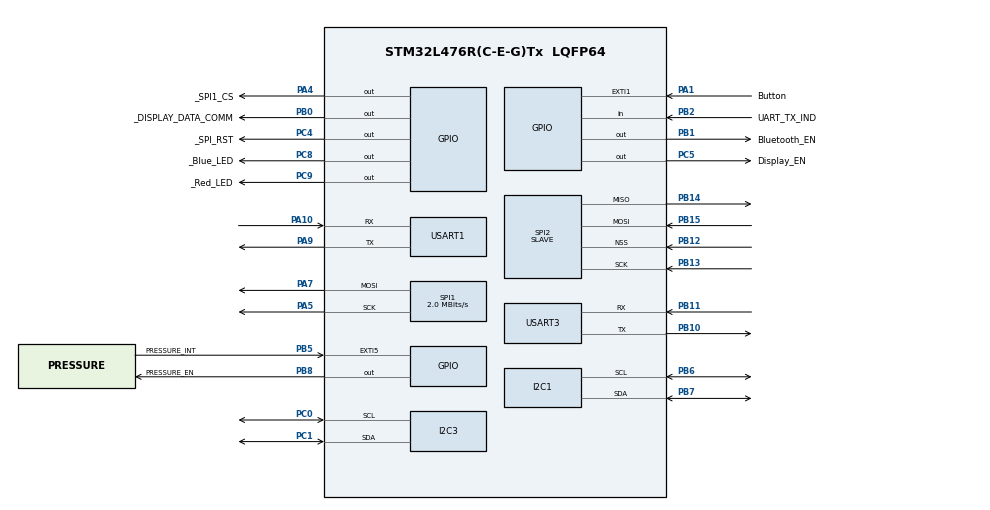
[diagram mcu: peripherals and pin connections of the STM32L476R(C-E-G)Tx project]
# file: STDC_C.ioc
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I2C1.Timing=0x00100D14
I2C3.Timing=0x00100D14
Mcu.Family=STM32L4
Mcu.Name=STM32L476R(C-E-G)Tx
Mcu.Package=LQFP64
NVIC.PriorityGroup=NVIC_PRIORITYGROUP_4
PA1.GPIO_Label=Button
PA1.GPIO_ModeDefaultEXTI=GPIO_MODE_IT_FALLING
PA1.GPIO_PuPd=GPIO_PULLUP
PA1.Signal=GPXTI1
PA10.Mode=Asynchronous
PA10.Signal=USART1_RX
PA13\ (JTMS-SWDIO).Mode=JTAG_5_pins
PA13\ (JTMS-SWDIO).Signal=SYS_JTMS-SWDIO
PA14\ (JTCK-SWCLK).Mode=JTAG_5_pins
PA14\ (JTCK-SWCLK).Signal=SYS_JTCK-SWCLK
PA15\ (JTDI).Mode=JTAG_5_pins
PA15\ (JTDI).Signal=SYS_JTDI
PA4.GPIO_Label=_SPI1_CS
PA4.Signal=GPIO_Output
PA5.Mode=TX_Only_Simplex_Unidirect_Master
PA5.Signal=SPI1_SCK
PA7.Mode=TX_Only_Simplex_Unidirect_Master
PA7.Signal=SPI1_MOSI
PA9.Mode=Asynchronous
PA9.Signal=USART1_TX
PB0.GPIO_Label=_DISPLAY_DATA_COMM
PB0.Signal=GPIO_Output
PB1.GPIO_Label=Bluetooth_EN
PB1.Signal=GPIO_Output
PB10.Mode=Asynchronous
PB10.Signal=USART3_TX
PB11.Mode=Asynchronous
PB11.Signal=USART3_RX
PB12.Mode=NSS_Signal_Hard_Input
PB12.Signal=SPI2_NSS
PB13.Mode=Full_Duplex_Slave
PB13.Signal=SPI2_SCK
PB14.Mode=Full_Duplex_Slave
PB14.Signal=SPI2_MISO
PB15.Mode=Full_Duplex_Slave
PB15.Signal=SPI2_MOSI
PB2.GPIO_Label=UART_TX_IND
PB2.Signal=GPIO_Input
PB3\ (JTDO-TRACESWO).Mode=JTAG_5_pins
PB3\ (JTDO-TRACESWO).Signal=SYS_JTDO-SWO
PB4\ (NJTRST).Mode=JTAG_5_pins
PB4\ (NJTRST).Signal=SYS_JTRST
PB5.GPIO_Label=PRESSURE_INT
PB5.Signal=GPXTI5
PB6.Mode=I2C
PB6.Signal=I2C1_SCL
PB7.Mode=I2C
PB7.Signal=I2C1_SDA
PB8.GPIO_Label=PRESSURE_EN
PB8.Signal=GPIO_Output
PC0.Mode=I2C
PC0.Signal=I2C3_SCL
PC1.Mode=I2C
PC1.Signal=I2C3_SDA
PC14-OSC32_IN\ (PC14).Mode=LSE-External-Oscillator
PC14-OSC32_IN\ (PC14).Signal=RCC_OSC32_IN
PC15-OSC32_OUT\ (PC15).Mode=LSE-External-Oscillator
PC15-OSC32_OUT\ (PC15).Signal=RCC_OSC32_OUT
PC4.GPIO_Label=_SPI_RST
PC4.Signal=GPIO_Output
PC5.GPIO_Label=Display_EN
PC5.Signal=GPIO_Output
PC8.GPIO_Label=_Blue_LED
PC8.Signal=GPIO_Output
PC9.GPIO_Label=_Red_LED
PC9.Signal=GPIO_Output
ProjectManager.HeapSize=0x200
ProjectManager.StackSize=0x400
ProjectManager.TargetToolchain=CMake
RCC.ADCFreq_Value=16000000
RCC.AHBFreq_Value=4000000
RCC.APB1Freq_Value=4000000
RCC.APB1TimFreq_Value=4000000
RCC.APB2Freq_Value=4000000
RCC.APB2TimFreq_Value=4000000
RCC.CortexFreq_Value=4000000
RCC.HCLKFreq_Value=4000000
RCC.HSE_VALUE=8000000
RCC.HSI_VALUE=16000000
RCC.MSI_VALUE=4000000
RCC.PLLM=4
RCC.PLLR=RCC_PLLR_DIV8
RCC.PLLSourceVirtual=RCC_PLLSOURCE_HSI
RCC.RTCClockSelection=RCC_RTCCLKSOURCE_LSE
RCC.SYSCLKFreq_VALUE=4000000
RCC.SYSCLKSource=RCC_SYSCLKSOURCE_PLLCLK
RCC.USBFreq_Value=16000000
RCC.VCOOutputFreq_Value=32000000
RTC.WakeUpClock-WakeUp=RTC_WAKEUPCLOCK_CK_SPRE_16BITS
RTC.WakeUpCounter-WakeUp=4
SPI1.BaudRatePrescaler=SPI_BAUDRATEPRESCALER_2
SPI1.CalculateBaudRate=2.0 MBits/s
SPI1.Direction=SPI_DIRECTION_2LINES
SPI1.Mode=SPI_MODE_MASTER
SPI1.VirtualType=VM_MASTER
SPI2.DataSize=SPI_DATASIZE_8BIT
SPI2.Direction=SPI_DIRECTION_2LINES
SPI2.Mode=SPI_MODE_SLAVE
SPI2.VirtualNSS=VM_NSSHARD
SPI2.VirtualType=VM_SLAVE
USART1.VirtualMode-Asynchronous=VM_ASYNC
USART3.VirtualMode-Asynchronous=VM_ASYNC
VP_RTC_VS_RTC_Activate.Mode=RTC_Enabled
VP_RTC_VS_RTC_Calendar.Mode=RTC_Calendar
VP_RTC_VS_RTC_WakeUp_intern.Mode=WakeUp
board=custom

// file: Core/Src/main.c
/* USER CODE BEGIN Header */
/**
  ******************************************************************************
  * @file           : main.c
  * @brief          : Main program body
  ******************************************************************************
  * @attention
  *
  * Copyright (c) 2026 STMicroelectronics.
  * All rights reserved.
  *
  * This software is licensed under terms that can be found in the LICENSE file
  * in the root directory of this software component.
  * If no LICENSE file comes with this software, it is provided AS-IS.
  *
  ******************************************************************************
  */
/* USER CODE END Header */
#include "main.h"

I2C_HandleTypeDef hi2c1;
I2C_HandleTypeDef hi2c3;

RTC_HandleTypeDef hrtc;

SPI_HandleTypeDef hspi1;
SPI_HandleTypeDef hspi2;

UART_HandleTypeDef huart1;
UART_HandleTypeDef huart3;

void SystemClock_Config(void);
static void MX_GPIO_Init(void);
static void MX_I2C1_Init(void);
static void MX_SPI1_Init(void);
static void MX_USART1_UART_Init(void);
static void MX_RTC_Init(void);
static void MX_USART3_UART_Init(void);
static void MX_SPI2_Init(void);
static void MX_I2C3_Init(void);

int main(void)
{

  /* MCU Configuration--------------------------------------------------------*/

  /* Reset of all peripherals, Initializes the Flash interface and the Systick. */
  HAL_Init();

  /* Configure the system clock */
  SystemClock_Config();

  /* Initialize all configured peripherals */
  MX_GPIO_Init();
  MX_I2C1_Init();
  MX_SPI1_Init();
  MX_USART1_UART_Init();
  MX_RTC_Init();
  MX_USART3_UART_Init();
  MX_SPI2_Init();
  MX_I2C3_Init();

  /* Infinite loop */
  while (1)
  {

  }
}

void SystemClock_Config(void)
{
  RCC_OscInitTypeDef RCC_OscInitStruct = {0};
  RCC_ClkInitTypeDef RCC_ClkInitStruct = {0};

  /** Configure the main internal regulator output voltage
  */
  if (HAL_PWREx_ControlVoltageScaling(PWR_REGULATOR_VOLTAGE_SCALE1) != HAL_OK)
  {
    Error_Handler();
  }

  /** Configure LSE Drive Capability
  */
  HAL_PWR_EnableBkUpAccess();
  __HAL_RCC_LSEDRIVE_CONFIG(RCC_LSEDRIVE_LOW);

  /** Initializes the RCC Oscillators according to the specified parameters
  * in the RCC_OscInitTypeDef structure.
  */
  RCC_OscInitStruct.OscillatorType = RCC_OSCILLATORTYPE_HSI|RCC_OSCILLATORTYPE_LSE;
  RCC_OscInitStruct.LSEState = RCC_LSE_ON;
  RCC_OscInitStruct.HSIState = RCC_HSI_ON;
  RCC_OscInitStruct.HSICalibrationValue = RCC_HSICALIBRATION_DEFAULT;
  RCC_OscInitStruct.PLL.PLLState = RCC_PLL_ON;
  RCC_OscInitStruct.PLL.PLLSource = RCC_PLLSOURCE_HSI;
  RCC_OscInitStruct.PLL.PLLM = 1;
  RCC_OscInitStruct.PLL.PLLN = 8;
  RCC_OscInitStruct.PLL.PLLP = RCC_PLLP_DIV7;
  RCC_OscInitStruct.PLL.PLLQ = RCC_PLLQ_DIV2;
  RCC_OscInitStruct.PLL.PLLR = RCC_PLLR_DIV4;
  if (HAL_RCC_OscConfig(&RCC_OscInitStruct) != HAL_OK)
  {
    Error_Handler();
  }

  /** Initializes the CPU, AHB and APB buses clocks
  */
  RCC_ClkInitStruct.ClockType = RCC_CLOCKTYPE_HCLK|RCC_CLOCKTYPE_SYSCLK
                              |RCC_CLOCKTYPE_PCLK1|RCC_CLOCKTYPE_PCLK2;
  RCC_ClkInitStruct.SYSCLKSource = RCC_SYSCLKSOURCE_PLLCLK;
  RCC_ClkInitStruct.AHBCLKDivider = RCC_SYSCLK_DIV1;
  RCC_ClkInitStruct.APB1CLKDivider = RCC_HCLK_DIV1;
  RCC_ClkInitStruct.APB2CLKDivider = RCC_HCLK_DIV1;

  if (HAL_RCC_ClockConfig(&RCC_ClkInitStruct, FLASH_LATENCY_1) != HAL_OK)
  {
    Error_Handler();
  }
}

static void MX_I2C1_Init(void)
{

  hi2c1.Instance = I2C1;
  hi2c1.Init.Timing = 0x00B07CB4;
  hi2c1.Init.OwnAddress1 = 0;
  hi2c1.Init.AddressingMode = I2C_ADDRESSINGMODE_7BIT;
  hi2c1.Init.DualAddressMode = I2C_DUALADDRESS_DISABLE;
  hi2c1.Init.OwnAddress2 = 0;
  hi2c1.Init.OwnAddress2Masks = I2C_OA2_NOMASK;
  hi2c1.Init.GeneralCallMode = I2C_GENERALCALL_DISABLE;
  hi2c1.Init.NoStretchMode = I2C_NOSTRETCH_DISABLE;
  if (HAL_I2C_Init(&hi2c1) != HAL_OK)
  {
    Error_Handler();
  }

  /** Configure Analogue filter
  */
  if (HAL_I2CEx_ConfigAnalogFilter(&hi2c1, I2C_ANALOGFILTER_ENABLE) != HAL_OK)
  {
    Error_Handler();
  }

  /** Configure Digital filter
  */
  if (HAL_I2CEx_ConfigDigitalFilter(&hi2c1, 0) != HAL_OK)
  {
    Error_Handler();
  }

}

static void MX_I2C3_Init(void)
{

  hi2c3.Instance = I2C3;
  hi2c3.Init.Timing = 0x00B07CB4;
  hi2c3.Init.OwnAddress1 = 0;
  hi2c3.Init.AddressingMode = I2C_ADDRESSINGMODE_7BIT;
  hi2c3.Init.DualAddressMode = I2C_DUALADDRESS_DISABLE;
  hi2c3.Init.OwnAddress2 = 0;
  hi2c3.Init.OwnAddress2Masks = I2C_OA2_NOMASK;
  hi2c3.Init.GeneralCallMode = I2C_GENERALCALL_DISABLE;
  hi2c3.Init.NoStretchMode = I2C_NOSTRETCH_DISABLE;
  if (HAL_I2C_Init(&hi2c3) != HAL_OK)
  {
    Error_Handler();
  }

  /** Configure Analogue filter
  */
  if (HAL_I2CEx_ConfigAnalogFilter(&hi2c3, I2C_ANALOGFILTER_ENABLE) != HAL_OK)
  {
    Error_Handler();
  }

  /** Configure Digital filter
  */
  if (HAL_I2CEx_ConfigDigitalFilter(&hi2c3, 0) != HAL_OK)
  {
    Error_Handler();
  }

}

static void MX_RTC_Init(void)
{

  RTC_TimeTypeDef sTime = {0};
  RTC_DateTypeDef sDate = {0};

  /** Initialize RTC Only
  */
  hrtc.Instance = RTC;
  hrtc.Init.HourFormat = RTC_HOURFORMAT_24;
  hrtc.Init.AsynchPrediv = 127;
  hrtc.Init.SynchPrediv = 255;
  hrtc.Init.OutPut = RTC_OUTPUT_DISABLE;
  hrtc.Init.OutPutRemap = RTC_OUTPUT_REMAP_NONE;
  hrtc.Init.OutPutPolarity = RTC_OUTPUT_POLARITY_HIGH;
  hrtc.Init.OutPutType = RTC_OUTPUT_TYPE_OPENDRAIN;
  if (HAL_RTC_Init(&hrtc) != HAL_OK)
  {
    Error_Handler();
  }

  /** Initialize RTC and set the Time and Date
  */
  sTime.Hours = 0x0;
  sTime.Minutes = 0x0;
  sTime.Seconds = 0x0;
  sTime.DayLightSaving = RTC_DAYLIGHTSAVING_NONE;
  sTime.StoreOperation = RTC_STOREOPERATION_RESET;
  if (HAL_RTC_SetTime(&hrtc, &sTime, RTC_FORMAT_BCD) != HAL_OK)
  {
    Error_Handler();
  }
  sDate.WeekDay = RTC_WEEKDAY_MONDAY;
  sDate.Month = RTC_MONTH_JANUARY;
  sDate.Date = 0x1;
  sDate.Year = 0x0;

  if (HAL_RTC_SetDate(&hrtc, &sDate, RTC_FORMAT_BCD) != HAL_OK)
  {
    Error_Handler();
  }

  /** Enable the WakeUp
  */
  if (HAL_RTCEx_SetWakeUpTimer(&hrtc, 4, RTC_WAKEUPCLOCK_CK_SPRE_16BITS) != HAL_OK)
  {
    Error_Handler();
  }

}

static void MX_SPI1_Init(void)
{

  /* SPI1 parameter configuration*/
  hspi1.Instance = SPI1;
  hspi1.Init.Mode = SPI_MODE_MASTER;
  hspi1.Init.Direction = SPI_DIRECTION_2LINES;
  hspi1.Init.DataSize = SPI_DATASIZE_4BIT;
  hspi1.Init.CLKPolarity = SPI_POLARITY_LOW;
  hspi1.Init.CLKPhase = SPI_PHASE_1EDGE;
  hspi1.Init.NSS = SPI_NSS_SOFT;
  hspi1.Init.BaudRatePrescaler = SPI_BAUDRATEPRESCALER_2;
  hspi1.Init.FirstBit = SPI_FIRSTBIT_MSB;
  hspi1.Init.TIMode = SPI_TIMODE_DISABLE;
  hspi1.Init.CRCCalculation = SPI_CRCCALCULATION_DISABLE;
  hspi1.Init.CRCPolynomial = 7;
  hspi1.Init.CRCLength = SPI_CRC_LENGTH_DATASIZE;
  hspi1.Init.NSSPMode = SPI_NSS_PULSE_ENABLE;
  if (HAL_SPI_Init(&hspi1) != HAL_OK)
  {
    Error_Handler();
  }

}

static void MX_SPI2_Init(void)
{

  /* SPI2 parameter configuration*/
  hspi2.Instance = SPI2;
  hspi2.Init.Mode = SPI_MODE_SLAVE;
  hspi2.Init.Direction = SPI_DIRECTION_2LINES;
  hspi2.Init.DataSize = SPI_DATASIZE_8BIT;
  hspi2.Init.CLKPolarity = SPI_POLARITY_LOW;
  hspi2.Init.CLKPhase = SPI_PHASE_1EDGE;
  hspi2.Init.NSS = SPI_NSS_HARD_INPUT;
  hspi2.Init.FirstBit = SPI_FIRSTBIT_MSB;
  hspi2.Init.TIMode = SPI_TIMODE_DISABLE;
  hspi2.Init.CRCCalculation = SPI_CRCCALCULATION_DISABLE;
  hspi2.Init.CRCPolynomial = 7;
  hspi2.Init.CRCLength = SPI_CRC_LENGTH_DATASIZE;
  hspi2.Init.NSSPMode = SPI_NSS_PULSE_DISABLE;
  if (HAL_SPI_Init(&hspi2) != HAL_OK)
  {
    Error_Handler();
  }

}

static void MX_USART1_UART_Init(void)
{

  huart1.Instance = USART1;
  huart1.Init.BaudRate = 115200;
  huart1.Init.WordLength = UART_WORDLENGTH_8B;
  huart1.Init.StopBits = UART_STOPBITS_1;
  huart1.Init.Parity = UART_PARITY_NONE;
  huart1.Init.Mode = UART_MODE_TX_RX;
  huart1.Init.HwFlowCtl = UART_HWCONTROL_NONE;
  huart1.Init.OverSampling = UART_OVERSAMPLING_16;
  huart1.Init.OneBitSampling = UART_ONE_BIT_SAMPLE_DISABLE;
  huart1.AdvancedInit.AdvFeatureInit = UART_ADVFEATURE_NO_INIT;
  if (HAL_UART_Init(&huart1) != HAL_OK)
  {
    Error_Handler();
  }

}

static void MX_USART3_UART_Init(void)
{

  huart3.Instance = USART3;
  huart3.Init.BaudRate = 115200;
  huart3.Init.WordLength = UART_WORDLENGTH_8B;
  huart3.Init.StopBits = UART_STOPBITS_1;
  huart3.Init.Parity = UART_PARITY_NONE;
  huart3.Init.Mode = UART_MODE_TX_RX;
  huart3.Init.HwFlowCtl = UART_HWCONTROL_NONE;
  huart3.Init.OverSampling = UART_OVERSAMPLING_16;
  huart3.Init.OneBitSampling = UART_ONE_BIT_SAMPLE_DISABLE;
  huart3.AdvancedInit.AdvFeatureInit = UART_ADVFEATURE_NO_INIT;
  if (HAL_UART_Init(&huart3) != HAL_OK)
  {
    Error_Handler();
  }

}

static void MX_GPIO_Init(void)
{
  GPIO_InitTypeDef GPIO_InitStruct = {0};

  /* GPIO Ports Clock Enable */
  __HAL_RCC_GPIOC_CLK_ENABLE();
  __HAL_RCC_GPIOA_CLK_ENABLE();
  __HAL_RCC_GPIOB_CLK_ENABLE();

  /*Configure GPIO pin Output Level */
  HAL_GPIO_WritePin(_SPI1_CS_GPIO_Port, _SPI1_CS_Pin, GPIO_PIN_RESET);

  /*Configure GPIO pin Output Level */
  HAL_GPIO_WritePin(GPIOC, _SPI_RST_Pin|Display_EN_Pin|_Blue_LED_Pin|_Red_LED_Pin, GPIO_PIN_RESET);

  /*Configure GPIO pin Output Level */
  HAL_GPIO_WritePin(GPIOB, _DISPLAY_DATA_COMM_Pin|PRESSURE_EN_Pin, GPIO_PIN_RESET);

  /*Configure GPIO pin : _SPI1_CS_Pin */
  GPIO_InitStruct.Pin = _SPI1_CS_Pin;
  GPIO_InitStruct.Mode = GPIO_MODE_OUTPUT_PP;
  GPIO_InitStruct.Pull = GPIO_NOPULL;
  GPIO_InitStruct.Speed = GPIO_SPEED_FREQ_LOW;
  HAL_GPIO_Init(_SPI1_CS_GPIO_Port, &GPIO_InitStruct);

  /*Configure GPIO pins : _SPI_RST_Pin Display_EN_Pin _Blue_LED_Pin _Red_LED_Pin */
  GPIO_InitStruct.Pin = _SPI_RST_Pin|Display_EN_Pin|_Blue_LED_Pin|_Red_LED_Pin;
  GPIO_InitStruct.Mode = GPIO_MODE_OUTPUT_PP;
  GPIO_InitStruct.Pull = GPIO_NOPULL;
  GPIO_InitStruct.Speed = GPIO_SPEED_FREQ_LOW;
  HAL_GPIO_Init(GPIOC, &GPIO_InitStruct);

  /*Configure GPIO pins : _DISPLAY_DATA_COMM_Pin PRESSURE_EN_Pin */
  GPIO_InitStruct.Pin = _DISPLAY_DATA_COMM_Pin|PRESSURE_EN_Pin;
  GPIO_InitStruct.Mode = GPIO_MODE_OUTPUT_PP;
  GPIO_InitStruct.Pull = GPIO_NOPULL;
  GPIO_InitStruct.Speed = GPIO_SPEED_FREQ_LOW;
  HAL_GPIO_Init(GPIOB, &GPIO_InitStruct);

  /*Configure GPIO pin : UART_TX_IND_Pin */
  GPIO_InitStruct.Pin = UART_TX_IND_Pin;
  GPIO_InitStruct.Mode = GPIO_MODE_INPUT;
  GPIO_InitStruct.Pull = GPIO_NOPULL;
  HAL_GPIO_Init(UART_TX_IND_GPIO_Port, &GPIO_InitStruct);

  /*Configure GPIO pin : PRESSURE_INT_Pin */
  GPIO_InitStruct.Pin = PRESSURE_INT_Pin;
  GPIO_InitStruct.Mode = GPIO_MODE_IT_RISING;
  GPIO_InitStruct.Pull = GPIO_NOPULL;
  HAL_GPIO_Init(PRESSURE_INT_GPIO_Port, &GPIO_InitStruct);

}

void Error_Handler(void)
{
  __disable_irq();
  while (1)
  {
  }
}
